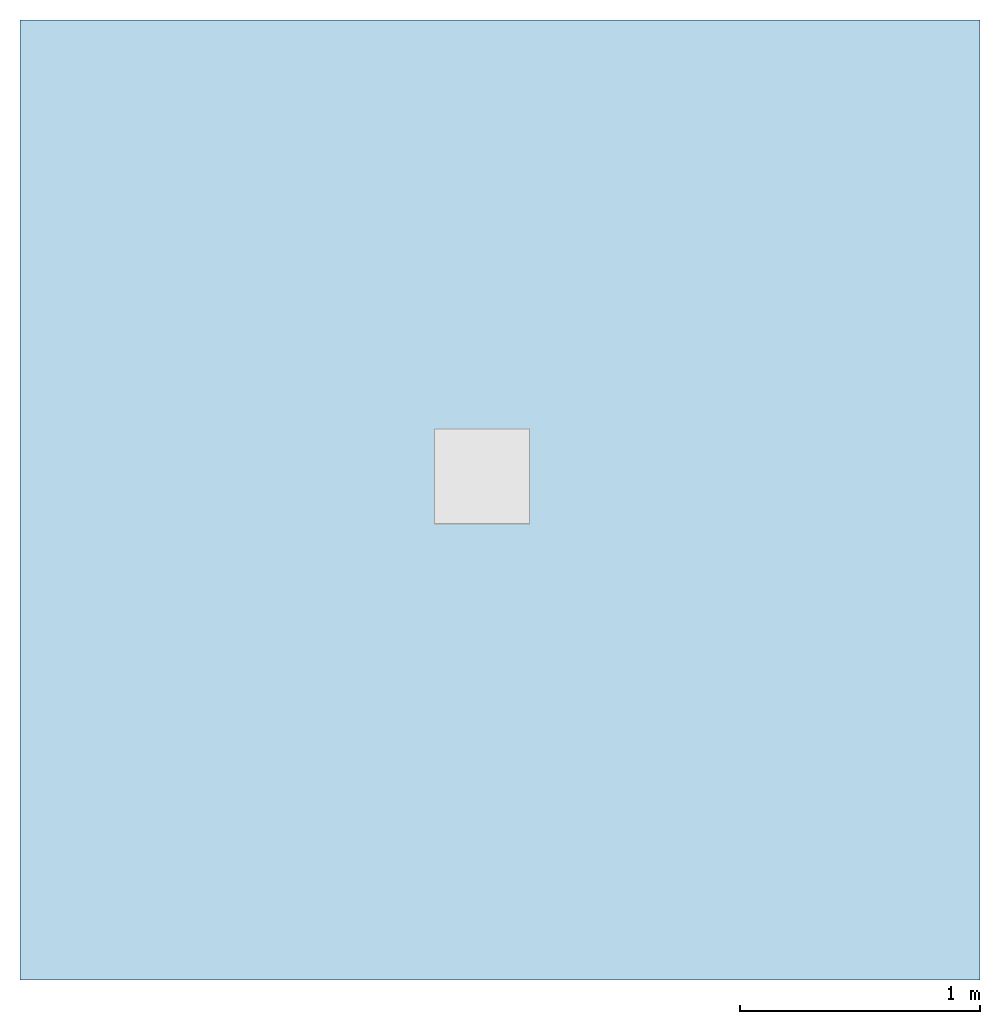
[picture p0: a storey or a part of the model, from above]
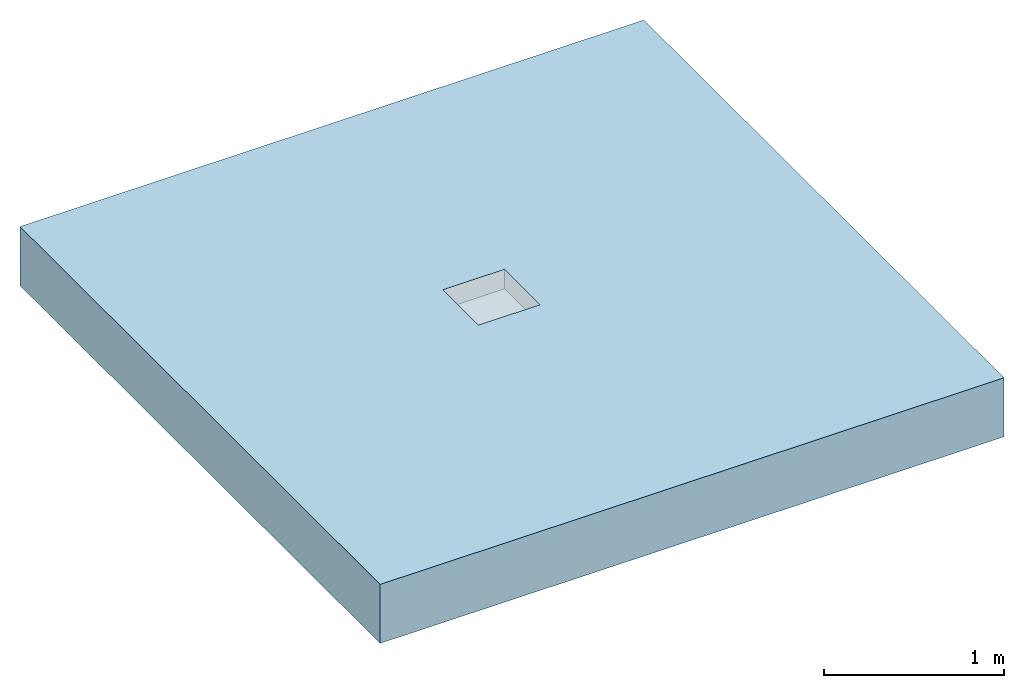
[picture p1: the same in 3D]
Properties of the parts of a building model (IFC2X3)

# File
Description: ViewDefinition [CoordinationView]
File name: Project Number
Time: 2014-06-06T11:09:40
Written by: The EXPRESS Data Manager Version 5.01.0100.02.64mod : 6 Jun 2012
Made in: 20130308_1515(x64) - Exporter 2014.0.2013.0308 - Default UI
Comment: STEP Physical File produced by: The EXPRESS Data Manager Version 5.01.0100.02.64mod : 6 Jun 2012 * Module: EDMstepFileFactory/EDMstandAlone * Creation date: Fri Jun 06 11:09:40 2014 * Host: IN-BLR-PC-0010 * Database: C:\Users\palleri\AppData\Local\Temp\{ECF0D15B-487C-4540-B042-6D02A83FBF62}\ifc * Database version: 5507 * Database creation date: Fri Jun 06 11:09:39 2014 * Schema: IFC2X3 * Model: DataRepository.ifc * Model creation date: Fri Jun 06 11:09:39 2014 * Header model: DataRepository.ifc_HeaderModel * Header model creation date: Fri Jun 06 11:09:39 2014 * EDMuser: sdai-user * EDMgroup: sdai-group * License ID and type: 5605 : Permanent license. Expiry date: * EDMstepFileFactory options: 020000

# IfcProject, Project Number
LongName: Project Name; Phase: Project Status

# IfcSite, Default
RefLatitude: 42, 21, 30, 344238; RefLongitude: -71, -3, -35, -194702; RefElevation: 0 mm

# IfcBuilding
Pset_BuildingCommon - NumberOfStoreys: 1
Other - Project Issue Date: Issue Date; Client Name: Owner; Project Status: Project Status; Project Address: ## Street City, State Zip; Project Name: Project Name; Project Number: Project Number

# IfcBuildingStorey, Level 1
LongName: Level 1; Elevation: 0 mm
Constraints - Elevation Base: Project Base Point; Elevation: 0 mm
Graphics - Line Weight: 1; Color: 0; Symbol: M_Level Head - Circle: M_Level Head - Circle; Line Pattern: Center; Symbol at End 2 Default: yes; Symbol at End 1 Default: no
Identity Data - Name: Level 1; Structural: no; Building Story: yes
Dimensions - Computation Height: 0 mm

# IfcFlowTerminal: 38803 - Access Frame - Adjustable Height - Invert Depth 75/105mm, ACO Freedeck Access Frame & Drain Duct (Accessories part 1) V1.27 - SS:38803 - Access Frame - Adjustable Height - Invert Depth 75/105mm:278221
In: Level 1
Material: Stainless Steel Grade 304
Model Properties - Access Frame Extension Product Code 38685: N/A; Access Frame Extension Product Code 38686: Load Class A15 - Access Frame Extension - Stainless Steel 304 - Invert Depth 50mm - 1.3kg; Access Grating Product Code 36760: Load Class A15 - Mesh Grating - 14mm x 30mm Mesh - Stainless Steel 304 - 3.5kg; Access Grating Product Code 36754: N/A; Access Frame Extension Product Code 38688: Load Class A15 - Access Frame Extension - Stainless Steel 304 - Invert Depth 75mm - 1.9kg; Access Frame Extension Product Code 38687: N/A
Dimensions - Access Frame Extension Position Height: 0 mm; Top Void Height End: -30 mm; Total Height: 134 mm; Top Void Height Start: -80 mm; Drainage Duct – Level below FFL: 30 mm; Height for Adjustable Access Frame: 105 mm; Base Height: 50 mm; Grating Start: 0 mm; Grating End: -20 mm; Drain Duct End: -100 mm
Identity Data - Mark: 15; Address: ACO Business Centre, Caxton Road, Bedford, MK41 0LF; Watermark2: This file is water marked and users are prohibited to reproduce, adapt, distribute this information; Watermark1: This file is the property of ACO Technologies PLC; Telephone: +44 (0)1462 816666; E-mail Technical: abdtechnical@aco.co.uk; Watermarked By: www.acobd.com; E-mail Sales: abdcommercial@aco.co.uk; Website: www.acobd.com; Watermarked With: BIM Manager Premium Suite; Manufacturer: ACO Building Drainage; Fax: +44 (0)1462 851490
Other - Fixed Access Frame Position Height: 80 mm; Adjustable Access Frame Position Height: 105 mm; Access Frame Extension Height: 50 mm; Drain Duct Vertical Height: 5000 mm; Access Frame Extension_Invert Depth 75mm: no; Access Frame Extension_Invert Depth 50mm: yes; Access Frame Extension: yes; Extension Removal Void: -2 mm; Grating: yes; Top void Size: 397 mm; Access Frame Adjustable Height: yes; Access Frame Fixed Height: no; Drain Duct: no
Constraints - Level: Level: Level 1; Moves With Nearby Elements: no
Construction - 38686_Access Frame Extension_Stainless Steel_Invert Depth 50mm: yes; 38688_Access Frame Extension_Stainless Steel_Invert Depth 75mm: no; 36760_Access Grating_Mesh Grating_Stainless Steel 304: yes
Phasing - Phase Created: New Construction
Pset_ManufacturerTypeInformation - Manufacturer: ACO Building Drainage
General - Load Class: A15; Weight (Kg): 3.1kg; Dimensions (LxWxH): 400 x 400 x 75/105; Price: POA - contact ACO; Channel Colour: Mid Grey; Product Code: 38803; Product Description: ACO Freedeck Access Frame - Adjustable; Product Range: ACO Freedeck; Product Standard: BS EN 1433:2002, CE marked; Installation Guidelines: X:\Electronic Literature\ABD Electronic Literature\Roof and Balcony Drainage\ACO Freedeck Brochure.pdf; Maintenance Guidelines: X:\Electronic Literature\ABD Electronic Literature\Roof and Balcony Drainage\ACO Freedeck Brochure.pdf; NBS Specification: NBS Section R10 Gravity Rainwater Drainage Systems, Subsection 365; Product Type: Linear Deck Drainage System; Channel Recycled Material Content: 60 - 70 %; Channel Material: Stainless Steel Grade 304; Channel Recyclable: Fully recyclable
Materials and Finishes - Material: Stainless Steel Grade 304

# IfcOpeningElement: Recess (2)
In: Level 1
Constraints - Room Bounding: yes; Height Offset From Level: 0 mm; Level: Level: Level 1; Related to Mass: no
Dimensions - Area: 16 m2; Thickness: 400 mm; Perimeter: 16000 mm; Volume: 6.37875 m3
Structural - Enable Analytical Model: no; Structural: no
Phasing - Phase Created: New Construction
Analytical Properties - Thermal Resistance (R): 0.382409; Thermal mass: 604440; Absorptance: 0.1; Roughness: 1; Heat Transfer Coefficient (U): 2.615
Graphics - Coarse Scale Fill Color: 0
Materials and Finishes - Structural Material: Concrete, Broom Finish
Construction - Default Thickness: 400 mm; Function: Interior

# IfcSlab: Floor:Generic Floor - 400mm, Floor:Generic Floor - 400mm:193825
In: Level 1
PredefinedType: FLOOR; Material: Concrete, Broom Finish 400 mm
Constraints - Room Bounding: yes; Height Offset From Level: 0 mm; Level: Level: Level 1; Related to Mass: no
Dimensions - Area: 16 m2; Thickness: 400 mm; Perimeter: 16000 mm; Volume: 6.37875 m3
Structural - Enable Analytical Model: no; Structural: no
Phasing - Phase Created: New Construction
Pset_SlabCommon - Reference: Generic Floor - 400mm; IsExternal: no; LoadBearing: yes; ThermalTransmittance: 2.615 kg/K/s3
Analytical Properties - Thermal Resistance (R): 0.382409; Thermal mass: 604440; Absorptance: 0.1; Roughness: 1; Heat Transfer Coefficient (U): 2.615
Graphics - Coarse Scale Fill Color: 0
Materials and Finishes - Structural Material: Concrete, Broom Finish
Construction - Default Thickness: 400 mm; Function: Interior
